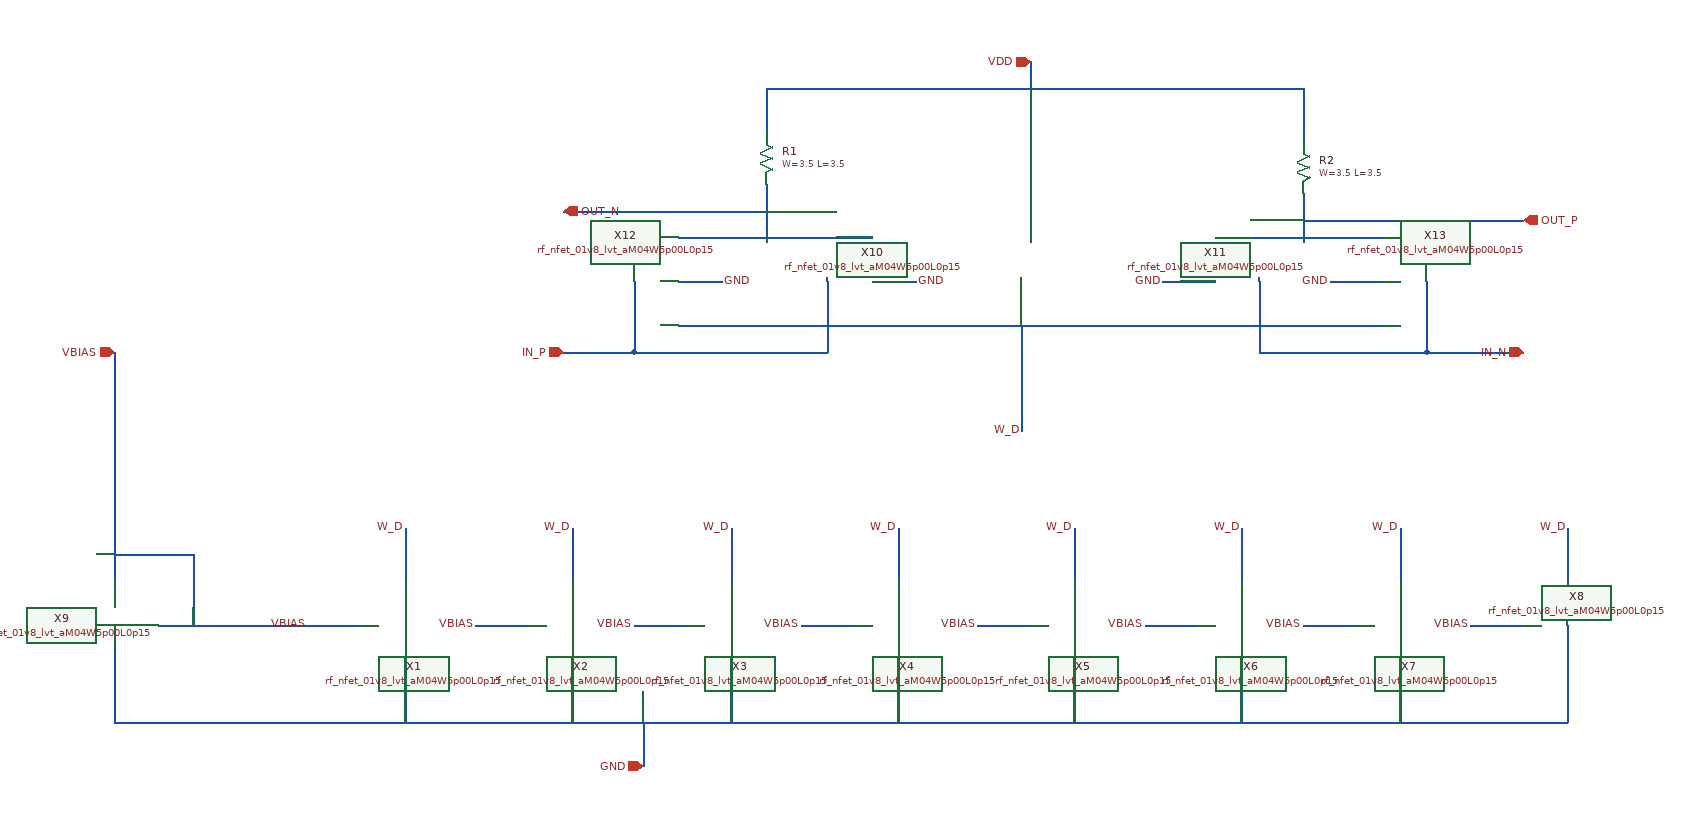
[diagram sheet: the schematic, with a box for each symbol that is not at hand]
v {xschem version=3.0.0 file_version=1.2 }
G {}
K {}
V {}
S {}
E {}
N 220 -110 220 0 {
lab=GND}
N 220 -220 220 -160 {
lab=W_D}
N 110 -110 170 -110 {
lab=VBIAS}
N 410 -110 410 0 {
lab=GND}
N 410 -220 410 -160 {
lab=W_D}
N 300 -110 360 -110 {
lab=VBIAS}
N 590 -110 590 0 {
lab=GND}
N 590 -220 590 -160 {
lab=W_D}
N 480 -110 540 -110 {
lab=VBIAS}
N 780 -110 780 0 {
lab=GND}
N 780 -220 780 -160 {
lab=W_D}
N 670 -110 730 -110 {
lab=VBIAS}
N 980 -110 980 0 {
lab=GND}
N 980 -220 980 -160 {
lab=W_D}
N 870 -110 930 -110 {
lab=VBIAS}
N 1170 -110 1170 0 {
lab=GND}
N 1170 -220 1170 -160 {
lab=W_D}
N 1060 -110 1120 -110 {
lab=VBIAS}
N 1350 -110 1350 0 {
lab=GND}
N 1350 -220 1350 -160 {
lab=W_D}
N 1240 -110 1300 -110 {
lab=VBIAS}
N 1540 -110 1540 0 {
lab=GND}
N 1540 -220 1540 -160 {
lab=W_D}
N 1430 -110 1490 -110 {
lab=VBIAS}
N -60 -110 110 -110 {
lab=VBIAS}
N -110 -110 -110 0 {
lab=GND}
N -110 -230 -110 -160 {
lab=VBIAS}
N -110 -190 -20 -190 {
lab=VBIAS}
N -20 -190 -20 -110 {
lab=VBIAS}
N 750 -500 800 -500 {
lab=GND}
N 1080 -500 1140 -500 {
lab=GND}
N 530 -500 580 -500 {
lab=GND}
N 1270 -500 1330 -500 {
lab=GND}
N 530 -450 1330 -450 {
lab=W_D}
N 530 -550 750 -550 {
lab=OUT_N}
N 1140 -550 1330 -550 {
lab=OUT_P}
N 700 -500 700 -420 {
lab=IN_P}
N 480 -500 480 -420 {
lab=IN_P}
N 480 -420 700 -420 {
lab=IN_P}
N 1190 -500 1190 -420 {
lab=IN_N}
N 1380 -500 1380 -420 {
lab=IN_N}
N 1190 -420 1380 -420 {
lab=IN_N}
N -110 0 1540 0 {
lab=GND}
N 630 -610 630 -550 {
lab=OUT_N}
N 1240 -600 1240 -550 {
lab=OUT_P}
N 630 -720 630 -670 {
lab=VDD}
N 630 -720 1240 -720 {
lab=VDD}
N 1240 -720 1240 -660 {
lab=VDD}
N 930 -750 930 -720 {
lab=VDD}
N 490 0 490 50 {
lab=GND}
N 1380 -420 1490 -420 {
lab=IN_N}
N 400 -420 480 -420 {
lab=IN_P}
N 1240 -570 1430 -570 {
lab=OUT_P}
N 400 -580 630 -580 {
lab=OUT_N}
N 1430 -570 1490 -570 {
lab=OUT_P}
N -110 -320 -110 -290 {
lab=VBIAS}
N 920 -450 920 -420 {
lab=W_D}
N 920 -360 920 -330 {
lab=W_D}
N -110 -290 -110 -230 {
lab=VBIAS}
N -110 -420 -110 -390 {
lab=VBIAS}
N -110 -330 -110 -320 {
lab=VBIAS}
N -110 -390 -110 -330 {
lab=VBIAS}
N 920 -420 920 -360 {
lab=W_D}
C {devices/lab_pin.sym} 110 -110 0 0 {name=l1 sig_type=std_logic lab=VBIAS}
C {devices/lab_pin.sym} 220 -220 0 0 {name=l2 sig_type=std_logic lab=W_D}
C {devices/lab_pin.sym} 300 -110 0 0 {name=l4 sig_type=std_logic lab=VBIAS}
C {devices/lab_pin.sym} 410 -220 0 0 {name=l5 sig_type=std_logic lab=W_D}
C {devices/lab_pin.sym} 480 -110 0 0 {name=l7 sig_type=std_logic lab=VBIAS}
C {devices/lab_pin.sym} 590 -220 0 0 {name=l8 sig_type=std_logic lab=W_D}
C {devices/lab_pin.sym} 670 -110 0 0 {name=l10 sig_type=std_logic lab=VBIAS}
C {devices/lab_pin.sym} 780 -220 0 0 {name=l11 sig_type=std_logic lab=W_D}
C {devices/lab_pin.sym} 870 -110 0 0 {name=l13 sig_type=std_logic lab=VBIAS}
C {devices/lab_pin.sym} 980 -220 0 0 {name=l14 sig_type=std_logic lab=W_D}
C {devices/lab_pin.sym} 1060 -110 0 0 {name=l16 sig_type=std_logic lab=VBIAS}
C {devices/lab_pin.sym} 1170 -220 0 0 {name=l17 sig_type=std_logic lab=W_D}
C {devices/lab_pin.sym} 1240 -110 0 0 {name=l19 sig_type=std_logic lab=VBIAS}
C {devices/lab_pin.sym} 1350 -220 0 0 {name=l20 sig_type=std_logic lab=W_D}
C {devices/lab_pin.sym} 1430 -110 0 0 {name=l22 sig_type=std_logic lab=VBIAS}
C {devices/lab_pin.sym} 1540 -220 0 0 {name=l23 sig_type=std_logic lab=W_D}
C {devices/iopin.sym} -110 -420 3 0 {name=p1 lab=VBIAS}
C {rf_nfet_01v8_lvt_aM04W5p00L0p15.sym} 680 -430 0 0 {name=X10}
C {rf_nfet_01v8_lvt_aM04W5p00L0p15.sym} 1210 -430 0 1 {name=X11}
C {devices/lab_pin.sym} 1080 -500 0 0 {name=l26 sig_type=std_logic lab=GND}
C {devices/lab_pin.sym} 800 -500 2 0 {name=l27 sig_type=std_logic lab=GND}
C {rf_nfet_01v8_lvt_aM04W5p00L0p15.sym} 460 -430 0 0 {name=X12}
C {devices/lab_pin.sym} 580 -500 2 0 {name=l28 sig_type=std_logic lab=GND}
C {rf_nfet_01v8_lvt_aM04W5p00L0p15.sym} 1400 -430 0 1 {name=X13}
C {devices/lab_pin.sym} 1270 -500 0 0 {name=l29 sig_type=std_logic lab=GND}
C {devices/lab_pin.sym} 920 -330 3 0 {name=l30 sig_type=std_logic lab=W_D}
C {devices/iopin.sym} 930 -750 3 0 {name=p2 lab=VDD}
C {devices/iopin.sym} 490 50 1 0 {name=p3 lab=GND}
C {devices/opin.sym} 1490 -570 0 0 {name=p4 lab=OUT_P}
C {devices/opin.sym} 400 -580 2 0 {name=p5 lab=OUT_N}
C {devices/ipin.sym} 400 -420 0 0 {name=p6 lab=IN_P}
C {devices/ipin.sym} 1490 -420 2 0 {name=p7 lab=IN_N}
C {sky130_fd_pr/res_generic_po.sym} 630 -640 0 0 {name=R1
W=3.5
L=3.5
model=res_generic_po
mult=1}
C {sky130_fd_pr/res_generic_po.sym} 1240 -630 0 0 {name=R2
W=3.5
L=3.5
model=res_generic_po
mult=1}
C {rf_nfet_01v8_lvt_aM04W5p00L0p15.sym} -40 -40 0 1 {name=X9}
C {rf_nfet_01v8_lvt_aM04W5p00L0p15.sym} 150 -40 0 0 {name=X1}
C {rf_nfet_01v8_lvt_aM04W5p00L0p15.sym} 340 -40 0 0 {name=X2}
C {rf_nfet_01v8_lvt_aM04W5p00L0p15.sym} 520 -40 0 0 {name=X3}
C {rf_nfet_01v8_lvt_aM04W5p00L0p15.sym} 710 -40 0 0 {name=X4}
C {rf_nfet_01v8_lvt_aM04W5p00L0p15.sym} 910 -40 0 0 {name=X5}
C {rf_nfet_01v8_lvt_aM04W5p00L0p15.sym} 1100 -40 0 0 {name=X6}
C {rf_nfet_01v8_lvt_aM04W5p00L0p15.sym} 1280 -40 0 0 {name=X7}
C {rf_nfet_01v8_lvt_aM04W5p00L0p15.sym} 1470 -40 0 0 {name=X8}
